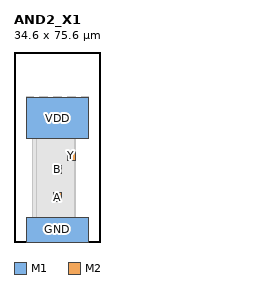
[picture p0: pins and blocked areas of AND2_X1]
MACRO AND2_X1
  CLASS CORE ;
  ORIGIN 0 0 ;
  SIZE 34.600 BY 75.600 ;
  SYMMETRY X Y ;
  SITE TR1um_access_site ;
  PIN VDD
    DIRECTION INOUT ;
    USE POWER ;
    PORT
      LAYER M1 ;
        RECT 5.000 41.000 29.600 57.600 ;
    END
  END VDD
  PIN GND
    DIRECTION INOUT ;
    USE GROUND ;
    PORT
      LAYER M1 ;
        RECT 5.000 0.000 29.600 9.800 ;
    END
  END GND
  PIN A
    DIRECTION INPUT ;
    USE SIGNAL ;
    PORT
      LAYER M2 ;
        RECT 15.600 16.100 19.000 19.500 ;
    END
  END A
  PIN B
    DIRECTION INPUT ;
    USE SIGNAL ;
    PORT
      LAYER M2 ;
        RECT 15.600 27.100 19.000 30.500 ;
    END
  END B
  PIN Y
    DIRECTION OUTPUT ;
    USE SIGNAL ;
    PORT
      LAYER M2 ;
        RECT 21.100 32.600 24.500 36.000 ;
    END
  END Y
  OBS
    LAYER M1 ;
      RECT 13.100 6.400 15.700 9.800 ;
    LAYER M1 ;
      RECT 10.600 16.100 19.000 19.500 ;
    LAYER M1 ;
      RECT 14.400 27.100 19.000 35.200 ;
    LAYER M1 ;
      RECT 7.400 6.400 20.900 51.200 ;
    LAYER M1 ;
      RECT 21.100 6.400 24.500 51.200 ;
    LAYER V1 ;
      RECT 4.800 0.000 7.800 2.800 ;
    LAYER V1 ;
      RECT 10.300 0.000 13.300 2.800 ;
    LAYER V1 ;
      RECT 15.800 0.000 18.800 2.800 ;
    LAYER V1 ;
      RECT 21.300 0.000 24.300 2.800 ;
    LAYER V1 ;
      RECT 26.800 0.000 29.800 2.800 ;
    LAYER V1 ;
      RECT 8.900 4.000 23.900 53.600 ;
    LAYER V1 ;
      RECT 4.800 54.800 7.800 57.800 ;
    LAYER V1 ;
      RECT 10.300 54.800 13.300 57.800 ;
    LAYER V1 ;
      RECT 15.800 54.800 18.800 57.800 ;
    LAYER V1 ;
      RECT 21.300 54.800 24.300 57.800 ;
    LAYER V1 ;
      RECT 26.800 54.800 29.800 57.800 ;
  END
END AND2_X1
